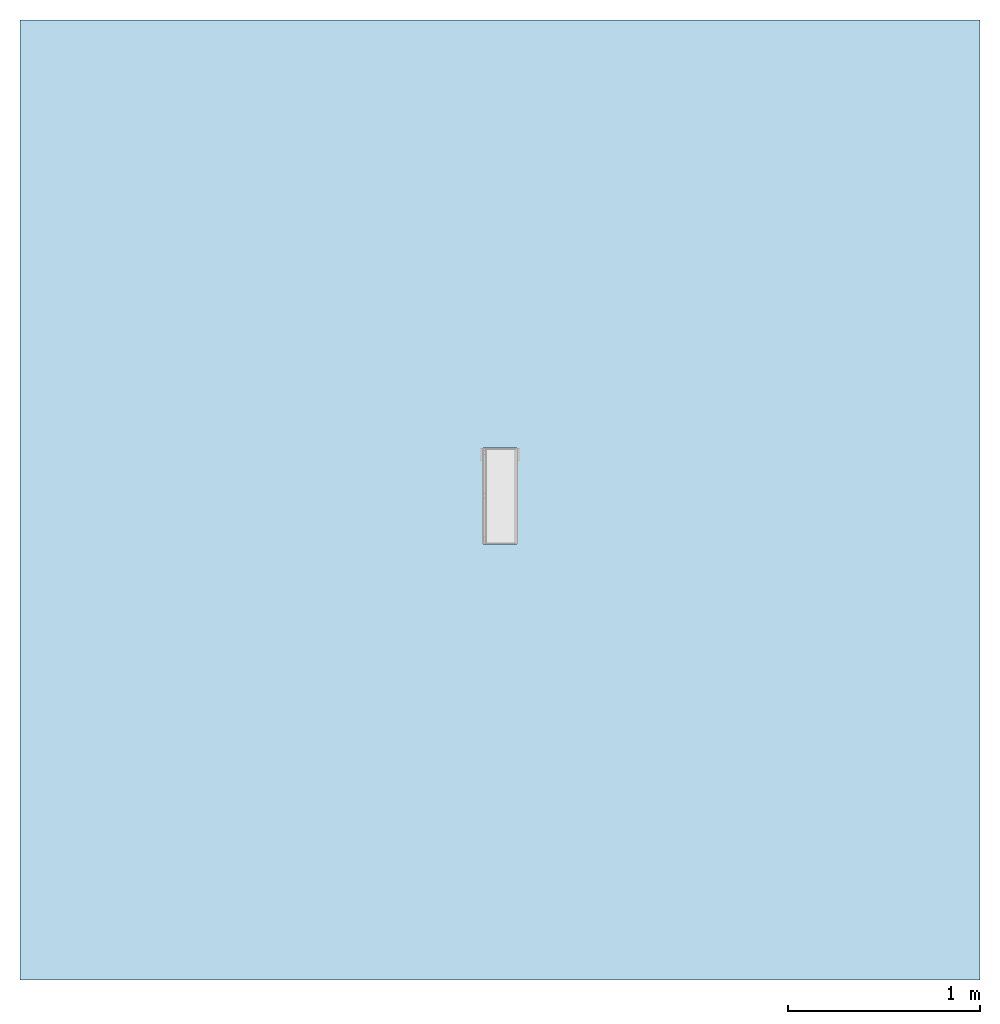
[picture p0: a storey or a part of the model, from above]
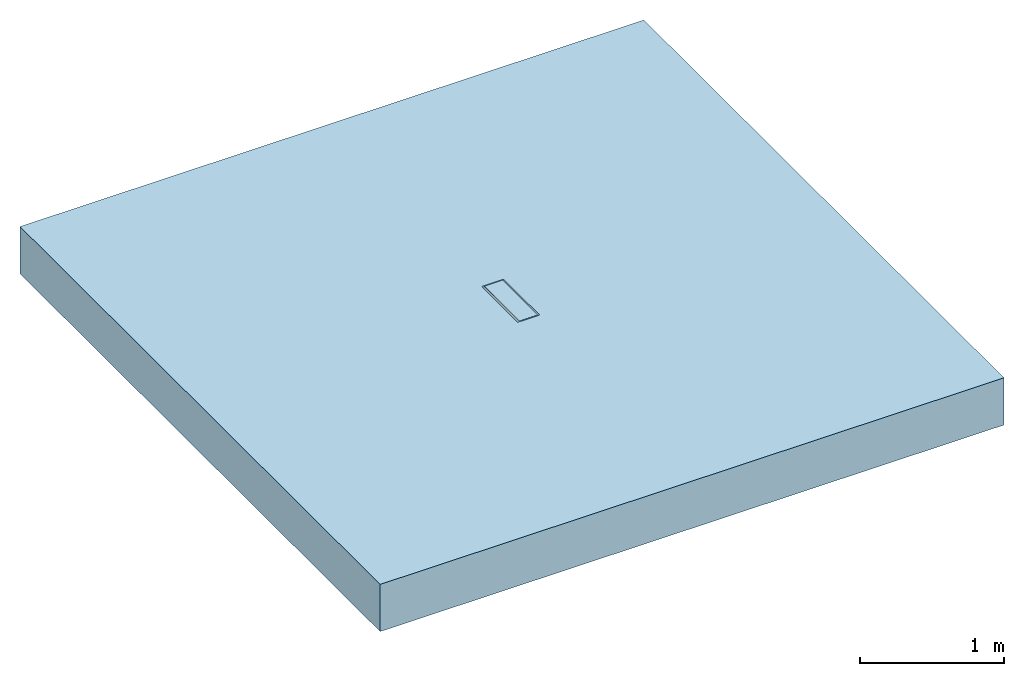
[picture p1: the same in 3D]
Properties of the parts of a building model (IFC2X3)

# File
Description: ViewDefinition [CoordinationView]
File name: 23158 - Universal Sump Unit - 500mm LG.ifc
Time: 2013-10-30T12:27:51
Written by: Autodesk Revit 2013
Made in: 20120221_2030(x64)

# IfcProject, Project Number
LongName: Project Name; Phase: Project Status

# IfcSite, Default
RefLatitude: 42, 21, 30, 344238; RefLongitude: -71, -3, -35, -194702; RefElevation: 0 mm

# IfcBuilding
Pset_BuildingCommon - NumberOfStoreys: 1
Other - Project Number: Project Number; Project Status: Project Status; Project Issue Date: Issue Date; Project Name: Project Name; Client Name: Owner; Project Address: ## Street City, State Zip

# IfcBuildingStorey, Level 1
LongName: Level 1; Elevation: 0 mm
Constraints - Elevation Base: 0; Elevation: 0 mm
Graphics - Line Weight: 1; Symbol: M_Level Head - Circle: M_Level Head - Circle; Symbol at End 2 Default: yes; Line Pattern: Center; Color: 0; Symbol at End 1 Default: no
Identity Data - Building Story: yes; Structural: no; Name: Level 1
Dimensions - Computation Height: 0 mm

# IfcBuildingElementProxy: 23158 - Universal Sump Unit - 500mm LG, Civil-Drainage-Channel-ACO-MultiDrain-M150D-Brickslot-Channel-System:23158 - Universal Sump Unit - 500mm LG:23158 - Universal Sump Unit - 500mm LG:196059
In: Level 1
Material: Plastic, Opaque Black, Steel, Galvanized, Phenolic Resin, Vienite® Synthetic Resin Concrete
Materials and Finishes - Edge Rail Finish: Pre-galvanised; Channel Colour: Brown; Edge Rail Material: Steel; Channel Material: Vienite® Synthetic Resin Concrete; Edge Rail Colour: Silver
Dimensions - FloorCut_Length: -500 mm; Brickslot Access Unit Void Bottom Depth: -105 mm; Custom_Void_Length: 500 mm; Brickslot Void Length: -500 mm; EndCap Position: 500 mm; Length: 1000 mm; Brickslot Access Unit Void Depth: 0 mm; Brickslot Grating Void Depth: 6500 mm; Volume: 20254474 mm3; Floor Cut Gap: 105 mm; Depth: 310 mm; InvDepth: 210 mm; End Cap Thickess: 3 mm; FloorCut_Width: 185 mm; Floor cut gap depth for access unit: 105 mm; Length Drain: -500 mm; EndCap_Height: -260 mm; FloorCut_Depth: 735 mm; FloorCut_HorPosition: 92.5 mm
Construction - 23159_Universal Endcap (Male End): no; 23177_Load Class C250 & D400_Brickslot_Access Unit_Galvanized Steel_500mm Long: yes; 23176_Load Class C250 & D400_Brickslot Grating_Galvanized Steel_500mm Long: no; 23159_Universal Endcap (Female End): no; 23175_Load Class C250 & D400_Brickslot Grating_Galvanized Steel_1000mm Long: no; Constant Depth Channel_1000: no; 23156_Shallow Depth Channel: no; 23157_Shallow Depth Channel with seal: no; Constant Depth Channel_500: no; Sump Unit: yes
Constraints - Moves With Nearby Elements: no; Level: Level: Level 1
Phasing - Phase Created: New Construction
Pset_BuildingElementProxyCommon - Reference: 23158 - Universal Sump Unit - 500mm LG
General - TagNumber: 0; SerialNumber: 0
Green Building Properties - Channel Recycled Material Content: 20% minimum; Edge Rail Recycled Material Content: Between 40% - 90%; Channel Recyclable: Fully recyclable; Edge Rail Recyclable: Fully recyclable
Model Properties - Brickslot Access Unit Product code 23177: Load Class C250/D400 - Brickslot Access Unit Galvanised steel - 500mm long x 105mm high - 10mm Slot -Intake area 10000mm²/m - 7.0kg; Brickslot Grating Product code 23175: N/A; End Cap Product code 23159: N/A; Brickslot Grating Product code 23176: N/A
Identity Data - Manufacturer: ACO Technologies plc - ACO Water Management Division; e-mail Technical: technical@aco.co.uk; Watermark 1: This file is the property of ACO Technologies PLC; Product Code: 23158; Price: POA - contact ACO; Watermarked By: www.aco.co.uk; Telephone: +44 (0)1462 816666; Cost: 0; Assembly Description: Rain Water Drainage; Type Comments: ACO MultiDrain M150D Sump Unit 500mm Long; Watermarked With: BIM Manager Premium Suite; Maintenance guidelines: http://www.aco.co.uk/download.php?id=173; Address: ACO Business Park, Hitchin Road, Shefford, Bedfordshire, United Kingdom SG17 5TE; OmniClass Title: Rainwater Removal; Fax: +44 (0)1462 815895; e-mail Sales: customersupport@aco.co.uk; Watermark 2: This file is water marked and users are prohibited to reproduce, adapt, distribute this information; Product brochure: http://www.aco.co.uk/download.php?id=173; Product Page URL: http://www.aco.co.uk/product_detail.php?id=58; Model: ACO MultiDrain MD Brickslot - M150D; URL: www.aco.co.uk; Assembly Code: D2040; Model Description: Channel drainage system; OmniClass Number: 23.70.50.24; Installation guidelines: http://www.aco.co.uk/download.php?id=173
Data - Concrete Surround Volume - Load Class B 125 - C 250 - Concrete Pavement: N/A; Concrete Surround Volume - Load Class D 400 - Concrete Pavement: N/A; Channel C.S.A: N/A; Pre-formed Outlet Ø: 110mm / 160mm / 200mm; Concrete Surround Volume - Load Class A 15 - Concrete Pavement: N/A; Invert Depth: 715mm; Load Class: A 15 - D 400; Product Weight: 44.0 Kg; Product Dimensions: 500mm x 185mm x 735mm (LxWxH); Installation - Concrete Grade: Refer to brochure; Hydraulic Performance: http://www.aco.co.uk/download.php?id=173; Product Standard: BS EN 1433:2002, CE marked; ACO Hydraulic Design Software: http://www.acodesign.co.uk
Other - Revision: 1; CreatedBy: www.aco.co.uk

# IfcOpeningElement: Opening (2)
In: Level 1
Dimensions - Area: 24984218 mm2; Volume: 9971055393 mm3; Thickness: 400 mm; Perimeter: 20000 mm
Constraints - Related to Mass: no; Level: Level: Level 1; Height Offset From Level: 0 mm; Room Bounding: yes
Structural - Structural: no; Enable Analytical Model: no
Phasing - Phase Created: New Construction
Graphics - Coarse Scale Fill Color: 0
Construction - Function: 0; Default Thickness: 400 mm
Analytical Properties - Thermal Resistance (R): 0.477897; Absorptance: 0.1; Roughness: 1; Heat Transfer Coefficient (U): 2.0925; Thermal mass: 543920
Materials and Finishes - Structural Material: Earth

# IfcSlab: Floor:Generic Floor - 400mm, Floor:Generic Floor - 400mm:193825
In: Level 1
PredefinedType: FLOOR; Material: Earth 400 mm
Dimensions - Area: 24984218 mm2; Volume: 9971055393 mm3; Thickness: 400 mm; Perimeter: 20000 mm
Constraints - Related to Mass: no; Level: Level: Level 1; Height Offset From Level: 0 mm; Room Bounding: yes
Structural - Structural: no; Enable Analytical Model: no
Phasing - Phase Created: New Construction
Pset_SlabCommon - Reference: Generic Floor - 400mm; IsExternal: no; LoadBearing: yes
Graphics - Coarse Scale Fill Color: 0
Construction - Function: 0; Default Thickness: 400 mm
Analytical Properties - Thermal Resistance (R): 0.477897; Absorptance: 0.1; Roughness: 1; Heat Transfer Coefficient (U): 2.0925; Thermal mass: 543920
Materials and Finishes - Structural Material: Earth
